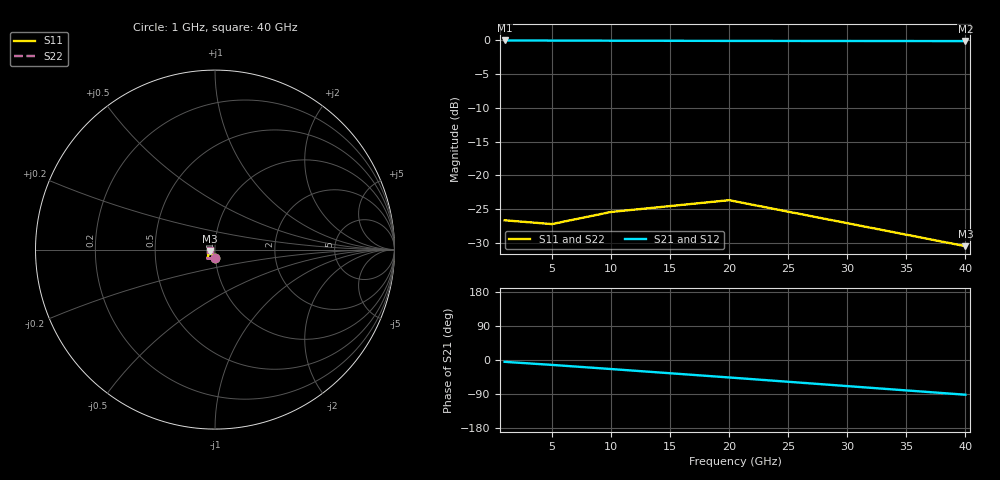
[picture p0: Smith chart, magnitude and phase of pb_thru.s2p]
! Generated by circuitRF - EM: Palace
! circuitRF-EM setup: g_thru_solids
! circuitRF-EM layout: thru/layout/thru.clay
! circuitRF-EM written: 2026-11-04 16:29:03Z
! circuitRF-EM geometry: 0bc7d4a451a6af78
! circuitRF-EM mesh: be36879526fbbc1a
! circuitRF-EM ports: e0915e1a10e1aaad
! circuitRF-EM model: Palace 0.18.1 (0dc74cd, schema 1-7-0)
! Port[1] = port/1
! Port[2] = port/2
! circuitRF-EM port 1: 'port/1' from 'airbox/zmin' to 'Metal1/1', wave (mode 1), 50 Ohm: Palace's S is referred to the mode's own impedance Z_PV, renormalised here to 50 Ohm; reference plane 0 um into the structure from the port face
! circuitRF-EM port 2: 'port/2' from 'airbox/zmin' to 'Metal1/1', wave (mode 1), 50 Ohm: Palace's S is referred to the mode's own impedance Z_PV, renormalised here to 50 Ohm; reference plane 0 um into the structure from the port face
! circuitRF-EM 3D mesh: 13,499 elements initially, 13,499 finally, 0 adaptive pass(es), element order 2
! circuitRF-EM 3D operating temperature: 20 C
! circuitRF-EM 3D run: preset Standard; 13499 -> 13499 tetrahedra; 94048 unknowns; 0 refinement pass(es); 6 frequency sample(s)
! circuitRF-EM 3D run cost: wall 452 s; Palace peak memory 1.6 GB
! circuitRF-EM 3D DC row: circuitRF conduction solve of the conductors, 4,203 elements, 0.51 s; ports as terminal pairs
! circuitRF-EM: re-running the EM setup rewrites this file. If circuitRF reports it as stale, the layout's cross-section changed after this file was written.
# GHz S RI R 50
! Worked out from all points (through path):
!   5 points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, 1 GHz to 40 GHz, reference 50 ohm
!   highest |S21| = -0.01 dB at 1 GHz (marker M1); lowest = -0.1 dB at 40 GHz (marker M2)
!   lowest |S11| = -30.5 dB at 40 GHz (marker M3), VSWR 1.06, Z = 47.2 - j0.733 ohm
!   |S11| at or under -10 dB: start of sweep to end of sweep
!   |S22| runs from -30.6 to -23.7 dB; largest |S21 - S12| = 1.2e-06
1  -0.00225 -0.0465  0.9955 -0.0836  0.9955 -0.0836  -0.00225 -0.0465
5  -0.00723 -0.043  0.9719 -0.2224  0.9719 -0.2224  -0.00728 -0.043
10  -0.0181 -0.0505  0.9101 -0.4019  0.9101 -0.4019  -0.0183 -0.0504
20  -0.0429 -0.0496  0.6879 -0.7139  0.6879 -0.7139  -0.0435 -0.0491
40  -0.0289 -0.00776  -0.0282 -0.9878  -0.0282 -0.9878  -0.029 -0.00469
